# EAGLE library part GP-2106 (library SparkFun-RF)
GP-2106 GPS SiRF IV

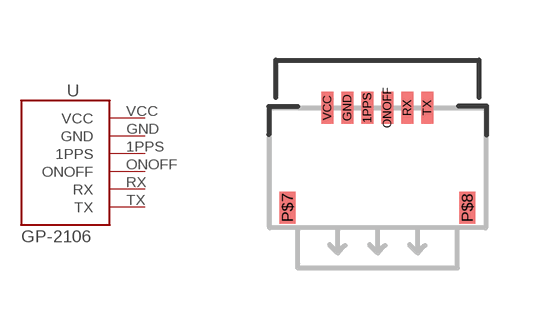
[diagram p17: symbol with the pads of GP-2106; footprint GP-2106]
Designator prefix U

## GP-2106  [GP-2106]
1PPS  1PPS
GND  GND
ONOFF  ONOFF
RX  RX
TX  TX
VCC  VCC

## Footprint GP-2106 (pad centres in mm)
smd 0.3 x 0.8: 1PPS -0.25,0; GND -0.75,0; ONOFF 0.25,0; RX 0.75,0; TX 1.25,0; VCC -1.25,0
smd 0.4 x 0.8: P$7 -2.25,-2.5; P$8 2.25,-2.5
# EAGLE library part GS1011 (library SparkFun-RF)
GainSpan GS1011M Low-Power Wireless SOC Wi-Fi Module

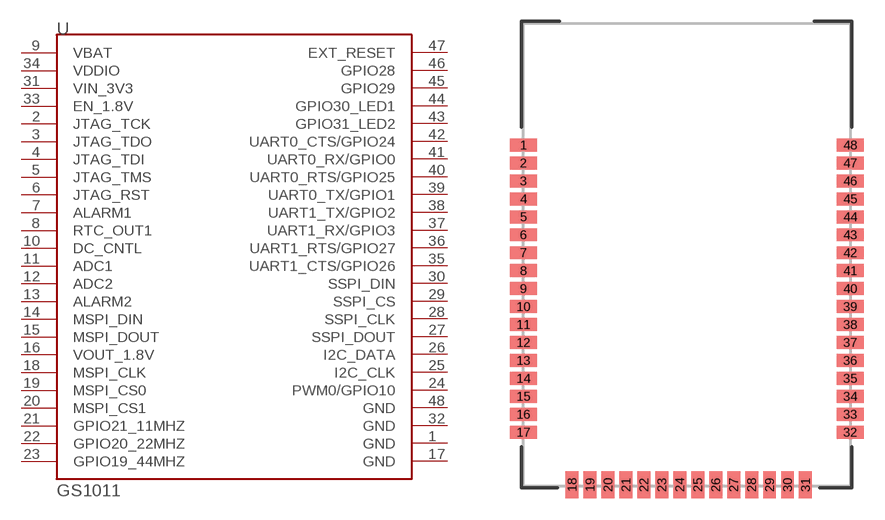
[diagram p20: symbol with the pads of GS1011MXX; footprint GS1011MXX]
Designator prefix U

## GS1011GS1011MXX  [GS1011MXX]
1  GND
2  JTAG_TCK
3  JTAG_TDO
4  JTAG_TDI
5  JTAG_TMS
6  JTAG_RST
7  ALARM1
8  RTC_OUT1
9  VBAT
10  DC_CNTL
11  ADC1
12  ADC2
13  ALARM2
14  MSPI_DIN
15  MSPI_DOUT
16  VOUT_1.8V
17  GND
18  MSPI_CLK
19  MSPI_CS0
20  MSPI_CS1
21  GPIO21_11MHZ
22  GPIO20_22MHZ
23  GPIO19_44MHZ
24  PWM0/GPIO10
25  I2C_CLK
26  I2C_DATA
27  SSPI_DOUT
28  SSPI_CLK
29  SSPI_CS
30  SSPI_DIN
31  VIN_3V3
32  GND
33  EN_1.8V
34  VDDIO
35  UART1_CTS/GPIO26
36  UART1_RTS/GPIO27
37  UART1_RX/GPIO3
38  UART1_TX/GPIO2
39  UART0_TX/GPIO1
40  UART0_RTS/GPIO25
41  UART0_RX/GPIO0
42  UART0_CTS/GPIO24
43  GPIO31_LED2
44  GPIO30_LED1
45  GPIO29
46  GPIO28
47  EXT_RESET
48  GND

## Footprint GS1011MXX (pad centres in mm)
SMD GS1011Mxx
smd 1.905 x 0.914: 1 -11.43,7.62; 2 -11.43,6.35; 3 -11.43,5.08; 4 -11.43,3.81; 5 -11.43,2.54; 6 -11.43,1.27; 7 -11.43,0; 8 -11.43,-1.27; 9 -11.43,-2.54; 10 -11.43,-3.81; 11 -11.43,-5.08; 12 -11.43,-6.35; 13 -11.43,-7.62; 14 -11.43,-8.89; 15 -11.43,-10.16; 16 -11.43,-11.43; 17 -11.43,-12.7; 32 11.684,-12.7; 33 11.684,-11.43; 34 11.684,-10.16; 35 11.684,-8.89; 36 11.684,-7.62; 37 11.684,-6.35; 38 11.684,-5.08; 39 11.684,-3.81; 40 11.684,-2.54; 41 11.684,-1.27; 42 11.684,0; 43 11.684,1.27; 44 11.684,2.54; 45 11.684,3.81; 46 11.684,5.08; 47 11.684,6.35; 48 11.684,7.62
smd 0.914 x 1.905: 18 -7.988,-16.421; 19 -6.718,-16.421; 20 -5.448,-16.421; 21 -4.178,-16.421; 22 -2.908,-16.421; 23 -1.638,-16.421; 24 -0.368,-16.421; 25 0.902,-16.421; 26 2.172,-16.421; 27 3.442,-16.421; 28 4.712,-16.421; 29 5.982,-16.421; 30 7.252,-16.421; 31 8.522,-16.421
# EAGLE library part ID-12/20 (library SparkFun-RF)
RFID reader for ID2, ID12, and ID20 Package

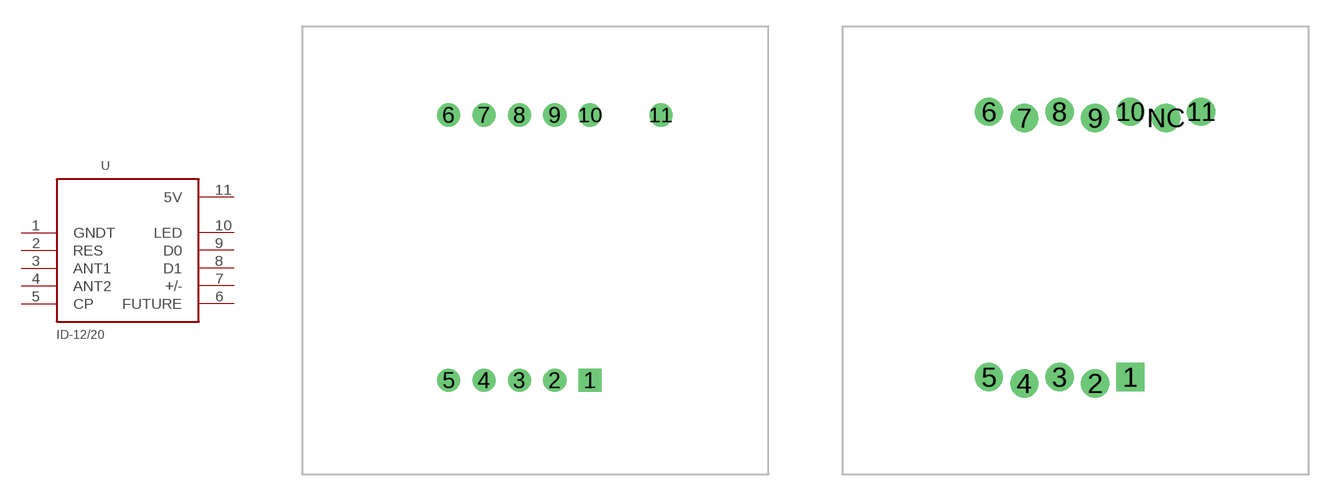
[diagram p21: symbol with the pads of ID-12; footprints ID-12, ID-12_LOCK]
Designator prefix -

## ID-12/20  [ID-12]
1  GNDT
2  RES
3  ANT1
4  ANT2
5  CP
6  FUTURE
7  +/-
8  D1
9  D0
10  LED
11  5V

## ID-12/20ID-12_LOCK  [ID-12_LOCK]
Pads as for ID-12

## ID-12/20SMD  [ID-12_SMD]
Pads as for ID-12

## Footprint ID-12 (pad centres in mm)
ID12 Footprint (works with ID2, ID12, and ID20)
drill 0.8 square: 1 16.255,5.32
drill 0.8: 2 14.255,5.32; 3 12.255,5.32; 4 10.255,5.32; 5 8.255,5.32; 6 8.255,20.32; 7 10.255,20.32; 8 12.255,20.32; 9 14.255,20.32; 10 16.255,20.32; 11 20.255,20.32

## Footprint ID-12_LOCK (pad centres in mm)
ID12 Footprint (works with ID2, ID12, and ID20)
drill 0.737 pad 1.6 square: 1 16.255,5.498
drill 0.737 pad 1.6: 2 14.255,5.142; 3 12.255,5.498; 4 10.255,5.142; 5 8.255,5.498; 6 8.255,20.498; 7 10.255,20.142; 8 12.255,20.498; 9 14.255,20.142; 10 16.255,20.498; 11 20.255,20.498; NC 18.268,20.142

## Footprint ID-12_SMD (pad centres in mm)
ID12 Footprint (works with ID2, ID12, and ID20)
smd 0.85 x 1.7: 1 16.248,3.81; 2 14.248,6.81; 3 12.248,3.81; 4 10.248,6.81; 5 8.248,3.81; 6 8.248,18.822; 7 10.248,21.822; 8 12.248,18.822; 9 14.248,21.822; 10 16.248,18.822; 11 20.248,18.822; NC 18.248,21.822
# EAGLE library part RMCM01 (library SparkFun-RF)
Polar Heart Rate Monitor module

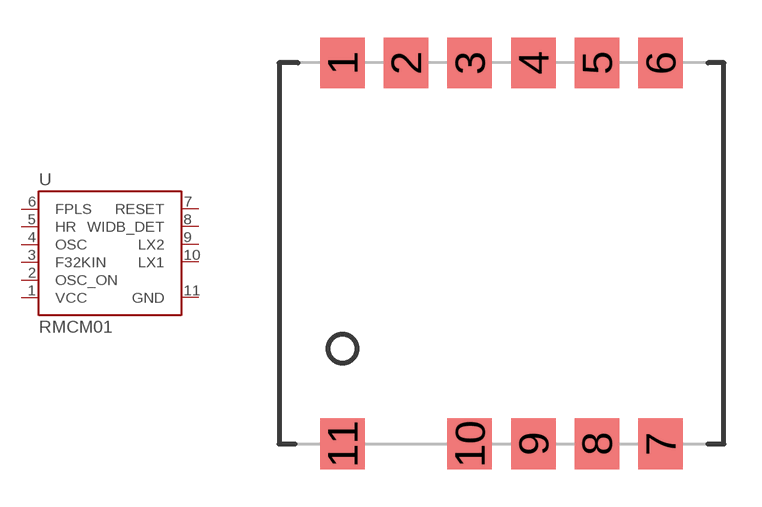
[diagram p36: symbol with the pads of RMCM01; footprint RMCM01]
Designator prefix -

## RMCM01SMD  [RMCM01]
1  VCC
2  OSC_ON
3  F32KIN
4  OSC
5  HR
6  FPLS
7  RESET
8  WIDB_DET
9  LX2
10  LX1
11  GND

## Footprint RMCM01 (pad centres in mm)
smd 1.778 x 2.032: 1 -6.35,7.62; 2 -3.81,7.62; 3 -1.27,7.62; 4 1.27,7.62; 5 3.81,7.62; 6 6.35,7.62; 7 6.35,-7.62; 8 3.81,-7.62; 9 1.27,-7.62; 10 -1.27,-7.62; 11 -6.35,-7.62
